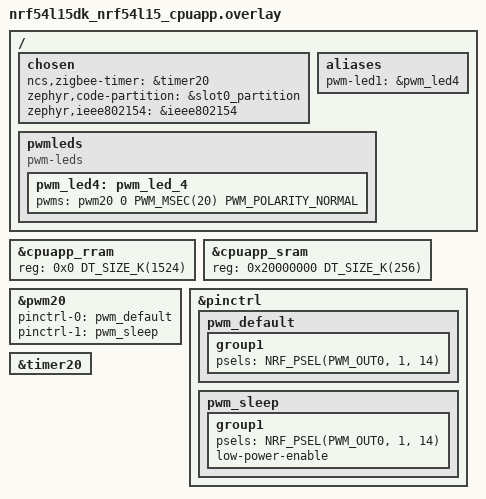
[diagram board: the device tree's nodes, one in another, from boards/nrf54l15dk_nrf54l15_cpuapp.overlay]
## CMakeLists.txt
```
#
# Copyright (c) 2026 Nordic Semiconductor ASA
#
# SPDX-License-Identifier: LicenseRef-Nordic-5-Clause
#

cmake_minimum_required(VERSION 3.20.0)

find_package(Zephyr REQUIRED HINTS $ENV{ZEPHYR_BASE})

project("Matter + Zigbee Light Bulb")

include(${ZEPHYR_CONNECTEDHOMEIP_MODULE_DIR}/config/nrfconnect/app/enable-gnu-std.cmake)
include(${ZEPHYR_NRF_MODULE_DIR}/samples/matter/common/cmake/source_common.cmake)
include(${ZEPHYR_NRF_MODULE_DIR}/samples/matter/common/cmake/data_model.cmake)
include(${ZEPHYR_NRF_MODULE_DIR}/samples/matter/common/cmake/zap_helpers.cmake)
ncs_get_zap_parent_dir(ZAP_PARENT_DIR)

target_include_directories(app PRIVATE
	src
	include
	${ZAP_PARENT_DIR}
)

target_compile_options(app PRIVATE -Wno-deprecated-declarations)

target_sources(app PRIVATE
	src/main.cpp
	src/app_task_zigbee.cpp
	src/app_task_matter.cpp
	src/zboss_mem_globals.c
	src/zcl_callbacks.cpp
	${CHIP_ROOT}/src/app/persistence/DeferredAttributePersistenceProvider.cpp
)

# LTO link: zb_memconfig.o from prebuilts is plain ELF (weak gc_*); strong gc_*
# in zb_mem_config_context.h must not be LTO bytecode or ld warns about symbol size.
if(CONFIG_LTO)
	set_source_files_properties(
		src/zboss_mem_globals.c
		PROPERTIES COMPILE_OPTIONS -fno-lto
	)
endif()

ncs_configure_data_model()
```

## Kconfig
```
#
# Copyright (c) 2026 Nordic Semiconductor ASA
#
# SPDX-License-Identifier: LicenseRef-Nordic-5-Clause
#

# Sample configuration used for Thread networking
if OPENTHREAD

choice OPENTHREAD_NORDIC_LIBRARY_CONFIGURATION
	default OPENTHREAD_NORDIC_LIBRARY_FTD
endchoice

choice OPENTHREAD_DEVICE_TYPE
	default OPENTHREAD_FTD
endchoice

endif # OPENTHREAD

if ZIGBEE_BT_DFU

config BT_DEVICE_NAME
	default "Zigbee_Bulb"

endif # ZIGBEE_BT_DFU

config MPSL_THREAD_COOP_PRIO
	default 8

source "$(ZEPHYR_CONNECTEDHOMEIP_MODULE_DIR)/config/nrfconnect/chip-module/Kconfig.features"
source "$(ZEPHYR_CONNECTEDHOMEIP_MODULE_DIR)/config/nrfconnect/chip-module/Kconfig.defaults"
source "$(ZEPHYR_NRF_MODULE_DIR)/samples/matter/common/src/Kconfig"

source "Kconfig.zephyr"
```

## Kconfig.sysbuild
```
#
# Copyright (c) 2024 Nordic Semiconductor
#
# SPDX-License-Identifier: LicenseRef-Nordic-5-Clause
#

config NRF_DEFAULT_IPC_RADIO
	default y

# Enable IEEE802.15.4 serialization to network core for Zigbee
config NETCORE_IPC_RADIO_IEEE802154
	default y if SOC_SERIES_NRF53

#### Bootloader
choice BOOTLOADER
	default BOOTLOADER_MCUBOOT
endchoice

if BOOTLOADER_MCUBOOT

#### DFU multi-image support
config DFU_MULTI_IMAGE_PACKAGE_BUILD
	default y

config DFU_MULTI_IMAGE_PACKAGE_APP
	default y

#### DFU dual core configuration
if SOC_SERIES_NRF53

config PM_EXTERNAL_FLASH_MCUBOOT_SECONDARY
	default y

config MCUBOOT_UPDATEABLE_IMAGES
	default 2

choice MCUBOOT_MODE
	default MCUBOOT_MODE_OVERWRITE_ONLY
endchoice

config SECURE_BOOT_NETCORE
	default y

config NETCORE_APP_UPDATE
	default y

config DFU_MULTI_IMAGE_PACKAGE_NET
	default y

endif # SOC_SERIES_NRF53

endif # BOOTLOADER_MCUBOOT

source "${ZEPHYR_BASE}/share/sysbuild/Kconfig"
```

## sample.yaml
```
sample:
  description: Combined Matter + Zigbee dimmable light bulb sample
  name: Matter + Zigbee Light bulb
common:
  tags:
    - ci_build
    - smoke
    - sysbuild
    - ci_samples_matter_zigbee
tests:
  sample.matter_zigbee.light_bulb:
    sysbuild: true
    build_only: true
    extra_args:
      - SNIPPET=ext_flash
    integration_platforms:
      - nrf54l15dk/nrf54l15/cpuapp
      - nrf54lm20dk/nrf54lm20b/cpuapp
    platform_allow:
      - nrf54l15dk/nrf54l15/cpuapp
      - nrf54lm20dk/nrf54lm20a/cpuapp
      - nrf54lm20dk/nrf54lm20b/cpuapp
  sample.matter_zigbee.light_bulb.int_flash:
    sysbuild: true
    build_only: true
    integration_platforms:
      - nrf54lm20dk/nrf54lm20b/cpuapp
    platform_allow:
      - nrf54lm20dk/nrf54lm20a/cpuapp
      - nrf54lm20dk/nrf54lm20b/cpuapp
  sample.matter_zigbee.light_bulb.release:
    sysbuild: true
    build_only: true
    extra_args:
      - SNIPPET=ext_flash
      - EXTRA_CONF_FILE=release.conf
    platform_allow:
      - nrf54l15dk/nrf54l15/cpuapp
      - nrf54lm20dk/nrf54lm20a/cpuapp
      - nrf54lm20dk/nrf54lm20b/cpuapp
    tags:
      - no_integration
  sample.matter_zigbee.light_bulb.touchlink:
    sysbuild: true
    build_only: true
    extra_args:
      - SNIPPET=ext_flash
      - CONFIG_ZIGBEE_TOUCHLINK_TARGET=y
    platform_allow:
      - nrf54l15dk/nrf54l15/cpuapp
      - nrf54lm20dk/nrf54lm20a/cpuapp
      - nrf54lm20dk/nrf54lm20b/cpuapp
    tags:
      - no_integration
  sample.matter_zigbee.light_bulb.zigbee_fota:
    sysbuild: true
    build_only: true
    extra_args:
      - SNIPPET=ext_flash
      - EXTRA_CONF_FILE=zigbee_fota.conf
    platform_allow:
      - nrf54l15dk/nrf54l15/cpuapp
      - nrf54lm20dk/nrf54lm20a/cpuapp
      - nrf54lm20dk/nrf54lm20b/cpuapp
    tags:
      - no_integration
```

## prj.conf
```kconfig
#
# Copyright (c) 2026 Nordic Semiconductor ASA
#
# SPDX-License-Identifier: LicenseRef-Nordic-5-Clause
#
# Debug configuration for combined Zigbee + Matter + Thread (PoC)
# Includes logging, console, and debug features

CONFIG_MATTER_ZIGBEE_ADD_ON=y

# Base sample configs
CONFIG_NCS_SAMPLES_DEFAULTS=y

CONFIG_UART_INTERRUPT_DRIVEN=y
CONFIG_SERIAL=y
CONFIG_GPIO=y
CONFIG_PWM=y

# Console
CONFIG_CONSOLE=y
CONFIG_UART_CONSOLE=y

# CONFIG_HEAP_MEM_POOL_SIZE=4096
CONFIG_MAIN_THREAD_PRIORITY=7

#######################
# Zigbee Configuration
#######################

CONFIG_ZIGBEE_ADD_ON=y
CONFIG_ZIGBEE_APP_UTILS=y
# Show Zigbee init/recovery logs (Device first start, network steering recovery).
CONFIG_ZIGBEE_APP_UTILS_LOG_LEVEL_INF=y
CONFIG_ZIGBEE_ROLE_ROUTER=y

# Scene extension
CONFIG_ZIGBEE_SCENES=y

# Enable DK LED and Buttons library
CONFIG_DK_LIBRARY=y

# This example requires more workqueue stack
CONFIG_SYSTEM_WORKQUEUE_STACK_SIZE=2048

CONFIG_ZBOSS_OSIF_LOG_LEVEL_INF=y
CONFIG_MATTER_ZIGBEE_COEXISTENCE_LOG_LEVEL_INF=y

#######################
# Zigbee FOTA Configuration
#######################

# FIXME: Disabled Zigbee FOTA for initial development
# # Enable Zigbee FOTA library
# CONFIG_ZIGBEE_FOTA=y
# CONFIG_ZIGBEE_FOTA_HW_VERSION=52
# CONFIG_ZIGBEE_FOTA_ENDPOINT=5
# CONFIG_MCUBOOT_IMGTOOL_SIGN_VERSION="1.0.0"
# CONFIG_ZIGBEE_FOTA_COMMENT="light_bulb_matter"

# # Ensure an MCUboot-compatible binary is generated.
# CONFIG_IMG_MANAGER=y
# CONFIG_STREAM_FLASH=y
# CONFIG_DFU_TARGET_MCUBOOT=y
# CONFIG_IMG_ERASE_PROGRESSIVELY=y
# CONFIG_ZIGBEE_FOTA_PROGRESS_EVT=y

# # Increase the number of RX buffers for FOTA
# CONFIG_NRF_802154_RX_BUFFERS=32

#######################
# Matter Configuration
#######################

# Enable CHIP (Matter)
CONFIG_CHIP=y
CONFIG_CHIP_PROJECT_CONFIG="include/chip_project_config.h"
CONFIG_CHIP_DEVICE_PRODUCT_NAME="Matter Zigbee Light Bulb"

# Configure ZAP file
CONFIG_NCS_SAMPLE_MATTER_ZAP_FILE_PATH="${APPLICATION_CONFIG_DIR}/src/matter_zap/light_bulb.zap"

# 32773 == 0x8005 (example lighting-app)
CONFIG_CHIP_DEVICE_PRODUCT_ID=32773
CONFIG_STD_CPP17=y

# Enable Matter pairing automatically on application start.
CONFIG_CHIP_ENABLE_PAIRING_AUTOSTART=y

# Enable Matter extended announcement and increase duration to 1 hour.
CONFIG_CHIP_BLE_EXT_ADVERTISING=y
CONFIG_CHIP_BLE_ADVERTISING_DURATION=60

CONFIG_BT_DEVICE_NAME="MatterZigbeeLb"

# Other settings
CONFIG_THREAD_NAME=y
CONFIG_MPU_STACK_GUARD=y
CONFIG_RESET_ON_FATAL_ERROR=n

# Reduce application size
CONFIG_USE_SEGGER_RTT=n

# Increase system workqueue stack for combined protocols (with Thread)
CONFIG_SYSTEM_WORKQUEUE_STACK_SIZE=6144

# Must be a preemptible priority (0–15), not cooperative (-1). With -1, ZBOSS is
# coop priority -1 and is outranked by MPSL Work (prio -8), so it never runs.
# State 128 = _THREAD_QUEUED (runnable); ZBOSS stays queued and never gets CPU.
CONFIG_ZBOSS_DEFAULT_THREAD_PRIORITY=1
CONFIG_ZBOSS_DEFAULT_THREAD_STACK_SIZE=6144

# Libc malloc arena required for Zigbee + Matter coexistence.
# - 0: no libc heap -> Matter init fails (malloc/calloc used during init).
# - -1: "all remaining RAM" -> on this build the computed heap extends past
#   valid RAM and triggers a precise data bus fault in sys_heap_init().
# - Positive value: static BSS heap of that size -> valid heap, no fault.
# Matter uses CHIP_MALLOC_SYS_HEAP for its own allocations; this arena
# covers libc malloc() used elsewhere (init, Zephyr, Zigbee, etc.).
CONFIG_COMMON_LIBC_MALLOC_ARENA_SIZE=-1

## PoC Configuration ##
# Keep Matter shell disabled to avoid getopt conflicts
CONFIG_CHIP_LIB_SHELL=n
CONFIG_NCS_SAMPLE_MATTER_TEST_SHELL=n

# Radio dispatcher 
CONFIG_NRF_802154_CALLBACKS_DISPATCHER=y

# We need it to disable ZBOSS thread
CONFIG_ZIGBEE_DEBUG_FUNCTIONS=y

CONFIG_CHIP_FACTORY_DATA_BUILD=y

# DFU over Bluetooth LE SMP
CONFIG_CHIP_DFU_OVER_BT_SMP=y
CONFIG_NCS_SAMPLE_MATTER_CUSTOM_BLUETOOTH_ADVERTISING=y
```

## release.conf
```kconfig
#
# Copyright (c) 2026 Nordic Semiconductor ASA
#
# SPDX-License-Identifier: LicenseRef-Nordic-5-Clause
#
# Release/size-optimization configuration for combined Zigbee + Matter + Thread (PoC)
# Disables logging, console, and other debug features to reduce flash usage

#######################
# Release Optimizations
#######################

# Disable all debug features
CONFIG_USE_SEGGER_RTT=n
CONFIG_SHELL=n
CONFIG_OPENTHREAD_SHELL=n
CONFIG_CONSOLE=n
CONFIG_UART_CONSOLE=n
CONFIG_SERIAL=n
CONFIG_UART_INTERRUPT_DRIVEN=n
CONFIG_LOG=n
CONFIG_LOG_MODE_MINIMAL=n
CONFIG_ASSERT_VERBOSE=n
CONFIG_ASSERT_NO_FILE_INFO=y
CONFIG_PRINTK=n
CONFIG_PRINTK_SYNC=n
CONFIG_BOOT_BANNER=n

# Enable LTO to decrease the flash usage
CONFIG_LTO=y
CONFIG_ISR_TABLES_LOCAL_DECLARATION=y

# Additional size optimizations
CONFIG_SIZE_OPTIMIZATIONS=y
CONFIG_COMPILER_OPT="-Os"
```

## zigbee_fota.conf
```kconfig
#
# Copyright (c) 2026 Nordic Semiconductor ASA
#
# SPDX-License-Identifier: LicenseRef-Nordic-5-Clause
#

# Enable Zigbee FOTA library
CONFIG_ZIGBEE_FOTA=y
CONFIG_ZIGBEE_FOTA_HW_VERSION=54
CONFIG_ZIGBEE_FOTA_ENDPOINT=5
CONFIG_MCUBOOT_IMGTOOL_SIGN_VERSION="1.0.0"
CONFIG_ZIGBEE_FOTA_COMMENT="light_bulb"

# Ensure an MCUboot-compatible binary is generated.
CONFIG_IMG_MANAGER=y
CONFIG_STREAM_FLASH=y
CONFIG_DFU_TARGET_MCUBOOT=y
CONFIG_IMG_ERASE_PROGRESSIVELY=y
CONFIG_ZIGBEE_FOTA_PROGRESS_EVT=y

# Increase the number of RX buffers for FOTA
CONFIG_NRF_802154_RX_BUFFERS=32
```

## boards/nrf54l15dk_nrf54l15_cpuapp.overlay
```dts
/*
 * Copyright (c) 2026 Nordic Semiconductor ASA
 *
 * SPDX-License-Identifier: LicenseRef-Nordic-5-Clause
 */

#include <nrf54l15dk_cpuapp_partitions.dtsi>

/ {
	chosen {
		ncs,zigbee-timer = &timer20;
		zephyr,code-partition = &slot0_partition;
		zephyr,ieee802154 = &ieee802154;
	};

	aliases {
		/* PWM on P1.14 (DK_LED4 / board LED 3). */
		pwm-led1 = &pwm_led4;
	};

	pwmleds {
		compatible = "pwm-leds";

		pwm_led4: pwm_led_4 {
			pwms = <&pwm20 0 PWM_MSEC(20) PWM_POLARITY_NORMAL>;
		};
	};
};

&cpuapp_rram {
	reg = <0x0 DT_SIZE_K(1524)>;
};

&cpuapp_sram {
	reg = <0x20000000 DT_SIZE_K(256)>;
	ranges = <0x0 0x20000000 0x40000>;
};

&pwm20 {
	status = "okay";
	pinctrl-0 = <&pwm_default>;
	pinctrl-1 = <&pwm_sleep>;
	pinctrl-names = "default", "sleep";
};

&pinctrl {
	pwm_default: pwm_default {
		group1 {
			psels = <NRF_PSEL(PWM_OUT0, 1, 14)>;
		};
	};

	pwm_sleep: pwm_sleep {
		group1 {
			psels = <NRF_PSEL(PWM_OUT0, 1, 14)>;
			low-power-enable;
		};
	};
};

&timer20 {
	status = "okay";
};
```

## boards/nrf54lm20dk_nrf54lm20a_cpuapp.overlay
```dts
/*
 * Copyright (c) 2026 Nordic Semiconductor ASA
 *
 * SPDX-License-Identifier: LicenseRef-Nordic-5-Clause
 */

#include <nrf54lm20_cpuapp_partitions.dtsi>
#include <nrf54lm20dk_cpuapp_partitions.dtsi>

/ {
	chosen {
		ncs,zigbee-timer = &timer23;
		ncs,zboss-trace-uart = &uart20;
	};

	aliases {
		/* PWM on P1.28 (DK_LED4 / board LED 3). */
		pwm-led1 = &pwm_led4;
	};

	pwmleds {
		compatible = "pwm-leds";
		pwm_led4: pwm_led_4 {
			pwms = <&pwm20 0 PWM_MSEC(20) PWM_POLARITY_NORMAL>;
		};
	};
};

&pwm20 {
	status = "okay";
	pinctrl-0 = <&pwm_default>;
	pinctrl-1 = <&pwm_sleep>;
	pinctrl-names = "default", "sleep";
};

&pinctrl {
	pwm_default: pwm_default {
		group1 {
			psels = <NRF_PSEL(PWM_OUT0, 1, 28)>;
		};
	};
	pwm_sleep: pwm_sleep {
		group1 {
			psels = <NRF_PSEL(PWM_OUT0, 1, 28)>;
			low-power-enable;
		};
	};
};

&timer23 {
	status = "okay";
};
```

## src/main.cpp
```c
/*
 * Copyright (c) 2026 Nordic Semiconductor ASA
 *
 * SPDX-License-Identifier: LicenseRef-Nordic-5-Clause
 */

/** @file
 *
 * @brief Matter + Zigbee light bulb entry point.
 */

#include "app_task_matter.h"
#include "app_task_zigbee.h"

#include <matter_zigbee_coexistence.h>
#include <matter_zigbee_ui.h>

namespace
{

void matter_start_cb(void)
{
	AppTask::Instance().StartApp();
}

bool app_ui_button_handler(uint32_t button_state, uint32_t has_changed, active_protocol_t active_protocol)
{
	/* Handle button events only for the active protocol. */
	if (active_protocol == PROTOCOL_ZIGBEE) {
		zb_button_handler(button_state, has_changed);
	}

	if (active_protocol == PROTOCOL_MATTER) {
		AppTask::ButtonEventHandler(button_state, has_changed);
	}

	return false;
}

const struct matter_zigbee_ui_callbacks ui_callbacks = {
	.on_button = app_ui_button_handler,
};

const struct matter_zigbee_coexistence_callbacks coexistence_cb = {
	matter_start_cb,
	ZigbeeStart,
	matter_zigbee_ui_register,
};

} /* namespace */

int main(void)
{
	matter_zigbee_ui_set_callbacks(&ui_callbacks);
	return matter_zigbee_coexistence_run(&coexistence_cb);
}
```

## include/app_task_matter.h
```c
/*
 * Copyright (c) 2026 Nordic Semiconductor ASA
 *
 * SPDX-License-Identifier: LicenseRef-Nordic-5-Clause
 */

#pragma once

#include "board/board.h"
#include "pwm/pwm_device.h"

#include <platform/CHIPDeviceLayer.h>

struct k_timer;
struct Identify;

enum class LightingActor : uint8_t { Remote, Button };

struct LightingEvent {
	uint8_t Action;
	LightingActor Actor;
};

class AppTask {
public:
	static AppTask &Instance()
	{
		static AppTask sAppTask;
		return sAppTask;
	};

	CHIP_ERROR StartApp();

	void UpdateClusterState();
	void InitPWMDDevice();
	Nrf::PWMDevice &GetPWMDevice() { return mPWMDevice; }

	static void ButtonEventHandler(Nrf::ButtonState state, Nrf::ButtonMask hasChanged);

private:
	CHIP_ERROR Init();

	static void LightingActionEventHandler(const LightingEvent &event);

	static void ActionInitiated(Nrf::PWMDevice::Action_t action, int32_t actor);
	static void ActionCompleted(Nrf::PWMDevice::Action_t action, int32_t actor);

	Nrf::PWMDevice mPWMDevice;
};
```

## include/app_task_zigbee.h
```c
/*
 * Copyright (c) 2026 Nordic Semiconductor ASA
 *
 * SPDX-License-Identifier: LicenseRef-Nordic-5-Clause
 */

#ifndef APP_TASK_ZIGBEE_H
#define APP_TASK_ZIGBEE_H 1

#include <stdint.h>

#ifdef __cplusplus
extern "C" {
#endif

int ZigbeeStart(void);

#ifdef CONFIG_MATTER_ZIGBEE_COEXISTENCE
/**
 * @brief Sample-specific button handler for Zigbee in combined builds.
 *
 * Invoked from the common UI module when a button event is received.
 * Processes button events when Zigbee is the active protocol and returns
 * immediately when Matter is active.
 *
 * @param button_state  Bitmask containing buttons state.
 * @param has_changed   Bitmask containing buttons that changed state.
 */
void zb_button_handler(uint32_t button_state, uint32_t has_changed);
#endif /* CONFIG_MATTER_ZIGBEE_COEXISTENCE */

#ifdef __cplusplus
}
#endif

#endif /* APP_TASK_ZIGBEE_H */
```

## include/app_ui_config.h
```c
/*
 * Copyright (c) 2026 Nordic Semiconductor ASA
 *
 * SPDX-License-Identifier: LicenseRef-Nordic-5-Clause
 */

#ifndef APP_UI_CONFIG_H_
#define APP_UI_CONFIG_H_

/** @file
 * @brief Light bulb sample UI configuration (buttons and LEDs).
 *
 * Common Matter + Zigbee UI buttons and LEDs are defined in
 * @ref matter_zigbee_ui_config.h. This file adds sample-specific mappings
 * shared by the Matter and Zigbee application tasks.
 */

#include <matter_zigbee_ui_config.h>

#include <zephyr/devicetree.h>

/** Button 3: toggle main light (Matter). */
#define APP_UI_BUTTON_LIGHT_TOGGLE DK_BTN3_MSK

/** Main light output on DK_LED3 (onboard LED 2), driven by PWM when enabled. */
#define APP_UI_LED_MAIN_LIGHT DK_LED3

/** PWM devicetree node for the main light (board overlay: pwm-led1 alias). */
#define APP_UI_PWM_LIGHT_NODE DT_ALIAS(pwm_led1)

#endif /* APP_UI_CONFIG_H_ */
```

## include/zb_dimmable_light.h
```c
/*
 * Copyright (c) 2024 Nordic Semiconductor ASA
 *
 * SPDX-License-Identifier: LicenseRef-Nordic-5-Clause
 */

#ifndef ZB_DIMMABLE_LIGHT_H
#define ZB_DIMMABLE_LIGHT_H 1

/**
 *  @defgroup ZB_DEFINE_DEVICE_DIMMABLE_LIGHT Dimmable Light
 *  @{
 *  @details
 *      - @ref ZB_ZCL_BASIC \n
 *      - @ref ZB_ZCL_IDENTIFY \n
 *      - @ref ZB_ZCL_SCENES \n
 *      - @ref ZB_ZCL_GROUPS \n
 *      - @ref ZB_ZCL_ON_OFF \n
 *      - @ref ZB_ZCL_LEVEL_CONTROL
 */

/** Dimmable Light Device ID */
#define ZB_DIMMABLE_LIGHT_DEVICE_ID 0x0101

/** Dimmable light device version */
#define ZB_DEVICE_VER_DIMMABLE_LIGHT 1

/** @cond internals_doc */

/** Dimmable Light IN (server) clusters number */
#define ZB_DIMMABLE_LIGHT_IN_CLUSTER_NUM 6

/** Dimmable Light OUT (client) clusters number */
#define ZB_DIMMABLE_LIGHT_OUT_CLUSTER_NUM 0

/** Dimmable light total (IN+OUT) cluster number */
#define ZB_DIMMABLE_LIGHT_CLUSTER_NUM (ZB_DIMMABLE_LIGHT_IN_CLUSTER_NUM + ZB_DIMMABLE_LIGHT_OUT_CLUSTER_NUM)

/** Number of attribute for reporting on Dimmable Light device */
#define ZB_DIMMABLE_LIGHT_REPORT_ATTR_COUNT (ZB_ZCL_ON_OFF_REPORT_ATTR_COUNT + ZB_ZCL_LEVEL_CONTROL_REPORT_ATTR_COUNT)

/** Continuous value change attribute count */
#define ZB_DIMMABLE_LIGHT_CVC_ATTR_COUNT 1

/** @endcond */ /* internals_doc */

/**
 * @brief Declare cluster list for Dimmable Light device
 * @param cluster_list_name - cluster list variable name
 * @param basic_attr_list - attribute list for Basic cluster
 * @param identify_attr_list - attribute list for Identify cluster
 * @param groups_attr_list - attribute list for Groups cluster
 * @param scenes_attr_list - attribute list for Scenes cluster
 * @param on_off_attr_list - attribute list for On/Off cluster
 * @param level_control_attr_list - attribute list for Level Control cluster
 */
#define ZB_DECLARE_DIMMABLE_LIGHT_CLUSTER_LIST(cluster_list_name, basic_attr_list, identify_attr_list,                 \
					       groups_attr_list, scenes_attr_list, on_off_attr_list,                   \
					       level_control_attr_list)                                                \
	zb_zcl_cluster_desc_t cluster_list_name[] = {                                                                  \
		ZB_ZCL_CLUSTER_DESC(ZB_ZCL_CLUSTER_ID_IDENTIFY, ZB_ZCL_ARRAY_SIZE(identify_attr_list, zb_zcl_attr_t),  \
				    (identify_attr_list), ZB_ZCL_CLUSTER_SERVER_ROLE, ZB_ZCL_MANUF_CODE_INVALID),      \
		ZB_ZCL_CLUSTER_DESC(ZB_ZCL_CLUSTER_ID_BASIC, ZB_ZCL_ARRAY_SIZE(basic_attr_list, zb_zcl_attr_t),        \
				    (basic_attr_list), ZB_ZCL_CLUSTER_SERVER_ROLE, ZB_ZCL_MANUF_CODE_INVALID),         \
		ZB_ZCL_CLUSTER_DESC(ZB_ZCL_CLUSTER_ID_SCENES, ZB_ZCL_ARRAY_SIZE(scenes_attr_list, zb_zcl_attr_t),      \
				    (scenes_attr_list), ZB_ZCL_CLUSTER_SERVER_ROLE, ZB_ZCL_MANUF_CODE_INVALID),        \
		ZB_ZCL_CLUSTER_DESC(ZB_ZCL_CLUSTER_ID_GROUPS, ZB_ZCL_ARRAY_SIZE(groups_attr_list, zb_zcl_attr_t),      \
				    (groups_attr_list), ZB_ZCL_CLUSTER_SERVER_ROLE, ZB_ZCL_MANUF_CODE_INVALID),        \
		ZB_ZCL_CLUSTER_DESC(ZB_ZCL_CLUSTER_ID_ON_OFF, ZB_ZCL_ARRAY_SIZE(on_off_attr_list, zb_zcl_attr_t),      \
				    (on_off_attr_list), ZB_ZCL_CLUSTER_SERVER_ROLE, ZB_ZCL_MANUF_CODE_INVALID),        \
		ZB_ZCL_CLUSTER_DESC(ZB_ZCL_CLUSTER_ID_LEVEL_CONTROL,                                                   \
				    ZB_ZCL_ARRAY_SIZE(level_control_attr_list, zb_zcl_attr_t),                         \
				    (level_control_attr_list), ZB_ZCL_CLUSTER_SERVER_ROLE, ZB_ZCL_MANUF_CODE_INVALID)  \
	}

/** @cond internals_doc */
/**
 * @brief Declare simple descriptor for Dimmable Light device
 * @param ep_name - endpoint variable name
 * @param ep_id - endpoint ID
 * @param in_clust_num - number of supported input clusters
 * @param out_clust_num - number of supported output clusters
 */
#define ZB_ZCL_DECLARE_HA_DIMMABLE_LIGHT_SIMPLE_DESC(ep_name, ep_id, in_clust_num, out_clust_num)                      \
	ZB_DECLARE_SIMPLE_DESC(in_clust_num, out_clust_num);                                                           \
	ZB_AF_SIMPLE_DESC_TYPE(in_clust_num, out_clust_num)                                                            \
	simple_desc_##ep_name = { ep_id,                                                                               \
				  ZB_AF_HA_PROFILE_ID,                                                                 \
				  ZB_DIMMABLE_LIGHT_DEVICE_ID,                                                         \
				  ZB_DEVICE_VER_DIMMABLE_LIGHT,                                                        \
				  0,                                                                                   \
				  in_clust_num,                                                                        \
				  out_clust_num,                                                                       \
				  {                                                                                    \
					  ZB_ZCL_CLUSTER_ID_BASIC,                                                     \
					  ZB_ZCL_CLUSTER_ID_IDENTIFY,                                                  \
					  ZB_ZCL_CLUSTER_ID_SCENES,                                                    \
					  ZB_ZCL_CLUSTER_ID_GROUPS,                                                    \
					  ZB_ZCL_CLUSTER_ID_ON_OFF,                                                    \
					  ZB_ZCL_CLUSTER_ID_LEVEL_CONTROL,                                             \
				  } }

/** @endcond */ /* internals_doc */

/**
 * @brief Declare endpoint for Dimmable Light device
 * @param ep_name - endpoint variable name
 * @param ep_id - endpoint ID
 * @param cluster_list - endpoint cluster list
 */
#define ZB_DECLARE_DIMMABLE_LIGHT_EP(ep_name, ep_id, cluster_list)                                                     \
	ZB_ZCL_DECLARE_HA_DIMMABLE_LIGHT_SIMPLE_DESC(ep_name, ep_id, ZB_DIMMABLE_LIGHT_IN_CLUSTER_NUM,                 \
						     ZB_DIMMABLE_LIGHT_OUT_CLUSTER_NUM);                               \
	ZBOSS_DEVICE_DECLARE_REPORTING_CTX(reporting_info##ep_name, ZB_DIMMABLE_LIGHT_REPORT_ATTR_COUNT);              \
	ZBOSS_DEVICE_DECLARE_LEVEL_CONTROL_CTX(cvc_alarm_info##ep_name, ZB_DIMMABLE_LIGHT_CVC_ATTR_COUNT);             \
	ZB_AF_DECLARE_ENDPOINT_DESC(ep_name, ep_id, ZB_AF_HA_PROFILE_ID, 0, NULL,                                      \
				    ZB_ZCL_ARRAY_SIZE(cluster_list, zb_zcl_cluster_desc_t), cluster_list,              \
				    (zb_af_simple_desc_1_1_t *)&simple_desc_##ep_name,                                 \
				    ZB_DIMMABLE_LIGHT_REPORT_ATTR_COUNT, reporting_info##ep_name,                      \
				    ZB_DIMMABLE_LIGHT_CVC_ATTR_COUNT, cvc_alarm_info##ep_name)

/** @} */

#endif /* ZB_DIMMABLE_LIGHT_H */
```

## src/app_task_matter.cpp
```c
/*
 * Copyright (c) 2026 Nordic Semiconductor ASA
 *
 * SPDX-License-Identifier: LicenseRef-Nordic-5-Clause
 */

#include "app_task_matter.h"

#include "app/matter_init.h"
#include "app/task_executor.h"

#if defined(CONFIG_PWM)
#include "pwm/pwm_device.h"
#endif

#include <matter_zigbee_ui_matter_identify.h>
#include <matter_zigbee_ui.h>
#include <matter_zigbee_ui_config.h>

#include "app_ui_config.h"

#include <zephyr/logging/log.h>

#include <app-common/zap-generated/attributes/Accessors.h>
#include <app/persistence/AttributePersistenceProviderInstance.h>
#include <app/persistence/DefaultAttributePersistenceProvider.h>
#include <app/persistence/DeferredAttributePersistenceProvider.h>
#include <app/server/Server.h>
#include <setup_payload/OnboardingCodesUtil.h>

#if defined(CONFIG_MATTER_ZIGBEE_COEXISTENCE)
#include <matter_zigbee_coexistence.h>
#endif

LOG_MODULE_DECLARE(app, CONFIG_CHIP_APP_LOG_LEVEL);

using namespace ::chip;
using namespace ::chip::app;
using namespace ::chip::DeviceLayer;

namespace
{
constexpr EndpointId kLightEndpointId = 1;
constexpr uint8_t kDefaultMinLevel = 0;
constexpr uint8_t kDefaultMaxLevel = 254;

MatterIdentifyCluster sIdentifyCluster(kLightEndpointId, true);

#if defined(CONFIG_PWM)
const struct pwm_dt_spec sLightPwmDevice = PWM_DT_SPEC_GET(APP_UI_PWM_LIGHT_NODE);
#endif

/* Define a custom attribute persister which makes actual write of the
 * CurrentLevel attribute value to the non-volatile storage only when it has
 * remained constant for 5 seconds. This is to reduce the flash wearout when the
 * attribute changes frequently as a result of MoveToLevel command.
 * DeferredAttribute object describes a deferred attribute, but also holds a
 * buffer with a value to be written, so it must live so long as the
 * DeferredAttributePersistenceProvider object.
 */
DeferredAttribute gCurrentLevelPersister(ConcreteAttributePath(kLightEndpointId, Clusters::LevelControl::Id,
							       Clusters::LevelControl::Attributes::CurrentLevel::Id));

/* Deferred persistence will be auto-initialized as soon as the default
 * persistence is initialized */
DefaultAttributePersistenceProvider gSimpleAttributePersistence;
DeferredAttributePersistenceProvider gDeferredAttributePersister(gSimpleAttributePersistence,
								 Span<DeferredAttribute>(&gCurrentLevelPersister, 1),
								 System::Clock::Milliseconds32(5000));

} /* namespace */

void AppTask::LightingActionEventHandler(const LightingEvent &event)
{
#if defined(CONFIG_PWM)
	Nrf::PWMDevice::Action_t action = Nrf::PWMDevice::INVALID_ACTION;
	int32_t actor = 0;
	if (event.Actor == LightingActor::Button) {
		action = Instance().mPWMDevice.IsTurnedOn() ? Nrf::PWMDevice::OFF_ACTION : Nrf::PWMDevice::ON_ACTION;
		actor = static_cast<int32_t>(event.Actor);
	}

	if (action == Nrf::PWMDevice::INVALID_ACTION || !Instance().mPWMDevice.InitiateAction(action, actor, NULL)) {
		LOG_INF("An action could not be initiated.");
	}
#else
	matter_zigbee_ui_led_toggle(APP_UI_LED_MAIN_LIGHT);
#endif
}

void AppTask::ButtonEventHandler(Nrf::ButtonState state, Nrf::ButtonMask hasChanged)
{
	if ((APP_UI_BUTTON_LIGHT_TOGGLE & hasChanged) & state) {
		Nrf::PostTask([] {
			LightingEvent event;
			event.Actor = LightingActor::Button;
			LightingActionEventHandler(event);
		});
	}
}

#if defined(CONFIG_PWM)
void AppTask::ActionInitiated(Nrf::PWMDevice::Action_t action, int32_t actor)
{
	if (action == Nrf::PWMDevice::ON_ACTION) {
		LOG_INF("Turn On Action has been initiated");
	} else if (action == Nrf::PWMDevice::OFF_ACTION) {
		LOG_INF("Turn Off Action has been initiated");
	} else if (action == Nrf::PWMDevice::LEVEL_ACTION) {
		LOG_INF("Level Action has been initiated");
	}
}

void AppTask::ActionCompleted(Nrf::PWMDevice::Action_t action, int32_t actor)
{
	if (action == Nrf::PWMDevice::ON_ACTION) {
		LOG_INF("Turn On Action has been completed");
	} else if (action == Nrf::PWMDevice::OFF_ACTION) {
		LOG_INF("Turn Off Action has been completed");
	} else if (action == Nrf::PWMDevice::LEVEL_ACTION) {
		LOG_INF("Level Action has been completed");
	}

	if (actor == static_cast<int32_t>(LightingActor::Button)) {
		Instance().UpdateClusterState();
	}
}
#endif /* CONFIG_PWM */

void AppTask::UpdateClusterState()
{
	SystemLayer().ScheduleLambda([this] {
#if defined(CONFIG_PWM)
		/* write the new on/off value */
		Protocols::InteractionModel::Status status =
			Clusters::OnOff::Attributes::OnOff::Set(kLightEndpointId, mPWMDevice.IsTurnedOn());
#else
		Protocols::InteractionModel::Status status = Clusters::OnOff::Attributes::OnOff::Set(
			kLightEndpointId, matter_zigbee_ui_led_get(APP_UI_LED_MAIN_LIGHT));
#endif
		if (status != Protocols::InteractionModel::Status::Success) {
			LOG_ERR("Updating on/off cluster failed: %x", to_underlying(status));
		}

#if defined(CONFIG_PWM)
		/* write the current level */
		status = Clusters::LevelControl::Attributes::CurrentLevel::Set(kLightEndpointId, mPWMDevice.GetLevel());
#else
		/* write the current level */
		if (matter_zigbee_ui_led_get(APP_UI_LED_MAIN_LIGHT)) {
			status = Clusters::LevelControl::Attributes::CurrentLevel::Set(kLightEndpointId, 100);
		} else {
			status = Clusters::LevelControl::Attributes::CurrentLevel::Set(kLightEndpointId, 0);
		}
#endif

		if (status != Protocols::InteractionModel::Status::Success) {
			LOG_ERR("Updating level cluster failed: %x", to_underlying(status));
		}
	});
}

void AppTask::InitPWMDDevice()
{
#if defined(CONFIG_PWM)
	/* Initialize lighting device (PWM) */
	uint8_t minLightLevel = kDefaultMinLevel;
	Clusters::LevelControl::Attributes::MinLevel::Get(kLightEndpointId, &minLightLevel);

	uint8_t maxLightLevel = kDefaultMaxLevel;
	Clusters::LevelControl::Attributes::MaxLevel::Get(kLightEndpointId, &maxLightLevel);

	Clusters::LevelControl::Attributes::CurrentLevel::TypeInfo::Type currentLevel;
	Clusters::LevelControl::Attributes::CurrentLevel::Get(kLightEndpointId, currentLevel);

	int ret =
		mPWMDevice.Init(&sLightPwmDevice, minLightLevel, maxLightLevel, currentLevel.ValueOr(kDefaultMaxLevel));
	if (ret != 0) {
		LOG_ERR("Failed to initialize PWD device.");
	}

	mPWMDevice.SetCallbacks(ActionInitiated, ActionCompleted);
#endif
}

CHIP_ERROR AppTask::Init()
{
	/* Initialize Matter stack */
	Nrf::Matter::InitData initData{};
	initData.mPostServerInitClbk = []() {
		app::SetAttributePersistenceProvider(&gDeferredAttributePersister);
		gSimpleAttributePersistence.Init(Nrf::Matter::GetPersistentStorageDelegate());
		return CHIP_NO_ERROR;
	};
#if defined(CONFIG_MATTER_ZIGBEE_COEXISTENCE)
	initData.mPreServerInitClbk = []() -> CHIP_ERROR {
		matter_zigbee_coexistence_pre_server_init();
		return CHIP_NO_ERROR;
	};
#endif
	ReturnErrorOnFailure(Nrf::Matter::PrepareServer(initData));

	ReturnErrorOnFailure(sIdentifyCluster.Init());

	ReturnErrorOnFailure(Nrf::Matter::StartServer());

#if defined(CONFIG_MATTER_ZIGBEE_COEXISTENCE)
	matter_zigbee_coexistence_on_server_started();
#endif

	return CHIP_NO_ERROR;
}

CHIP_ERROR AppTask::StartApp()
{
	ReturnErrorOnFailure(Init());

	while (true) {
		Nrf::DispatchNextTask();
	}

	return CHIP_NO_ERROR;
}
```

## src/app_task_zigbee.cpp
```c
/*
 * Copyright (c) 2026 Nordic Semiconductor ASA
 *
 * SPDX-License-Identifier: LicenseRef-Nordic-5-Clause
 */

/** @file
 *
 * @brief Simple Zigbee light bulb implementation.
 */

#include "app_task_zigbee.h"

#ifdef CONFIG_MATTER_ZIGBEE_COEXISTENCE
#include <matter_zigbee_coexistence.h>
#include <matter_zigbee_protocol_state.h>
#endif

#include <matter_zigbee_ui_config.h>
#include <matter_zigbee_ui.h>

#include "app_ui_config.h"

#include <soc.h>
#include <zephyr/device.h>
#include <zephyr/drivers/pwm.h>
#include <zephyr/kernel.h>
#include <zephyr/logging/log.h>
#include <zephyr/sys/util.h>
#ifdef CONFIG_ZIGBEE_SCENES
#include <zephyr/settings/settings.h>
#endif
#include <zephyr/types.h>

#if defined(CONFIG_ZIGBEE_FOTA) || defined(CONFIG_ZIGBEE_BT_DFU)
#include <zephyr/dfu/mcuboot.h>
#endif

#include <ram_pwrdn.h>

extern "C" {
#include "zb_dimmable_light.h"
#include <dk_buttons_and_leds.h>
#include <zb_nrf_platform.h>
#include <zboss_api.h>
#include <zboss_api_addons.h>
#include <zigbee/zigbee_app_utils.h>
#include <zigbee/zigbee_error_handler.h>
#ifdef CONFIG_ZIGBEE_SCENES
#include <zigbee/zigbee_zcl_scenes.h>
#endif
#if CONFIG_ZIGBEE_FOTA
#include <zigbee/zigbee_fota.h>
#endif
#ifdef CONFIG_ZIGBEE_BT_DFU
#include <zigbee/zigbee_bt_dfu.h>
#endif
}

#if CONFIG_ZIGBEE_FOTA
#include <zephyr/sys/reboot.h>
#endif

/* Device endpoint, used to receive light controlling commands. */
#define DIMMABLE_LIGHT_ENDPOINT 10

/* Version of the application software (1 byte). */
#define BULB_INIT_BASIC_APP_VERSION 01

/* Version of the implementation of the Zigbee stack (1 byte). */
#define BULB_INIT_BASIC_STACK_VERSION 10

/* Version of the hardware of the device (1 byte). */
#define BULB_INIT_BASIC_HW_VERSION 11

/* Manufacturer name (32 bytes). */
#define BULB_INIT_BASIC_MANUF_NAME "Nordic"

/* Model number assigned by manufacturer (32-bytes long string). */
#define BULB_INIT_BASIC_MODEL_ID "Dimable_Light_v0.1"

/* First 8 bytes specify the date of manufacturer of the device
 * in ISO 8601 format (YYYYMMDD). The rest (8 bytes) are manufacturer specific.
 */
#define BULB_INIT_BASIC_DATE_CODE "20200329"

/* Type of power sources available for the device.
 * For possible values see section 3.2.2.2.8 of ZCL specification.
 */
#define BULB_INIT_BASIC_POWER_SOURCE ZB_ZCL_BASIC_POWER_SOURCE_DC_SOURCE

/* Describes the physical location of the device (16 bytes).
 * May be modified during commissioning process.
 */
#define BULB_INIT_BASIC_LOCATION_DESC "Office desk"

/* Describes the type of physical environment.
 * For possible values see section 3.2.2.2.10 of ZCL specification.
 */
#define BULB_INIT_BASIC_PH_ENV ZB_ZCL_BASIC_ENV_UNSPECIFIED

#if DT_NODE_HAS_STATUS(APP_UI_PWM_LIGHT_NODE, okay)
static const struct pwm_dt_spec led_pwm = PWM_DT_SPEC_GET(APP_UI_PWM_LIGHT_NODE);
#else
#error "Choose supported PWM driver"
#endif

/* Led PWM period, calculated for 100 Hz signal - in microseconds. */
#define LED_PWM_PERIOD_US (USEC_PER_SEC / 100U)

#ifndef ZB_ROUTER_ROLE
#error Define ZB_ROUTER_ROLE to compile router source code.
#endif

LOG_MODULE_REGISTER(app, CONFIG_CHIP_APP_LOG_LEVEL);

/* Main application customizable context.
 * Stores all settings and static values.
 */
typedef struct {
	zb_zcl_basic_attrs_ext_t basic_attr;
	zb_zcl_identify_attrs_t identify_attr;
	zb_zcl_scenes_attrs_t scenes_attr;
	zb_zcl_groups_attrs_t groups_attr;
	zb_zcl_on_off_attrs_t on_off_attr;
	zb_zcl_level_control_attrs_t level_control_attr;
} bulb_device_ctx_t;

/* Zigbee device application context storage. */
static bulb_device_ctx_t dev_ctx;

/* Last non-zero brightness used when turning on with CurrentLevel == 0. */
static zb_uint8_t s_last_on_level = ZB_ZCL_LEVEL_CONTROL_LEVEL_MAX_VALUE;

ZB_ZCL_DECLARE_IDENTIFY_ATTRIB_LIST(identify_attr_list, &dev_ctx.identify_attr.identify_time);

ZB_ZCL_DECLARE_GROUPS_ATTRIB_LIST(groups_attr_list, &dev_ctx.groups_attr.name_support);

ZB_ZCL_DECLARE_SCENES_ATTRIB_LIST(scenes_attr_list, &dev_ctx.scenes_attr.scene_count,
				  &dev_ctx.scenes_attr.current_scene, &dev_ctx.scenes_attr.current_group,
				  &dev_ctx.scenes_attr.scene_valid, &dev_ctx.scenes_attr.name_support);

ZB_ZCL_DECLARE_BASIC_ATTRIB_LIST_EXT(basic_attr_list, &dev_ctx.basic_attr.zcl_version, &dev_ctx.basic_attr.app_version,
				     &dev_ctx.basic_attr.stack_version, &dev_ctx.basic_attr.hw_version,
				     dev_ctx.basic_attr.mf_name, dev_ctx.basic_attr.model_id,
				     dev_ctx.basic_attr.date_code, &dev_ctx.basic_attr.power_source,
				     dev_ctx.basic_attr.location_id, &dev_ctx.basic_attr.ph_env,
				     dev_ctx.basic_attr.sw_ver);

/* On/Off cluster attributes additions data */
ZB_ZCL_DECLARE_ON_OFF_ATTRIB_LIST(on_off_attr_list, &dev_ctx.on_off_attr.on_off);

ZB_ZCL_DECLARE_LEVEL_CONTROL_ATTRIB_LIST(level_control_attr_list, &dev_ctx.level_control_attr.current_level,
					 &dev_ctx.level_control_attr.remaining_time);

ZB_DECLARE_DIMMABLE_LIGHT_CLUSTER_LIST(dimmable_light_clusters, basic_attr_list, identify_attr_list, groups_attr_list,
				       scenes_attr_list, on_off_attr_list, level_control_attr_list);

ZB_DECLARE_DIMMABLE_LIGHT_EP(dimmable_light_ep, DIMMABLE_LIGHT_ENDPOINT, dimmable_light_clusters);

#ifndef CONFIG_ZIGBEE_FOTA
ZBOSS_DECLARE_DEVICE_CTX_1_EP(dimmable_light_ctx, dimmable_light_ep);
#else

#if DIMMABLE_LIGHT_ENDPOINT == CONFIG_ZIGBEE_FOTA_ENDPOINT
#error "Light bulb and Zigbee OTA endpoints should be different."
#endif

extern zb_af_endpoint_desc_t zigbee_fota_client_ep;
ZBOSS_DECLARE_DEVICE_CTX_2_EP(dimmable_light_ctx, zigbee_fota_client_ep, dimmable_light_ep);
#endif /* CONFIG_ZIGBEE_FOTA */

/**@brief Starts identifying the device.
 *
 * @param  bufid  Unused parameter, required by ZBOSS scheduler API.
 */
static void start_identifying(zb_bufid_t bufid)
{
	ZVUNUSED(bufid);

	if (ZB_JOINED()) {
		/* Check if endpoint is in identifying mode,
		 * if not, put desired endpoint in identifying mode.
		 */
		if (dev_ctx.identify_attr.identify_time == ZB_ZCL_IDENTIFY_IDENTIFY_TIME_DEFAULT_VALUE) {
			zb_ret_t zb_err_code = zb_bdb_finding_binding_target(DIMMABLE_LIGHT_ENDPOINT);

			if (zb_err_code == RET_OK) {
				LOG_INF("Enter identify mode");
			} else if (zb_err_code == RET_INVALID_STATE) {
				LOG_WRN("RET_INVALID_STATE - Cannot enter identify mode");
			} else {
				ZB_ERROR_CHECK(zb_err_code);
			}
		} else {
			LOG_INF("Cancel identify mode");
			zb_bdb_finding_binding_target_cancel();
		}
	} else {
		LOG_WRN("Device not in a network - cannot enter identify mode");
	}
}

/**@brief Implementation of button event handling for the Zigbee bulb.
 *
 * In combined Matter+Zigbee builds the handler returns early when Matter is
 * the active protocol so Matter's own handlers (registered by Board::Init())
 * keep full ownership of the buttons.
 */
static void zb_button_handler_impl(uint32_t button_state, uint32_t has_changed)
{
	if (MATTER_ZIGBEE_UI_BUTTON_IDENTIFY & has_changed) {
		if (MATTER_ZIGBEE_UI_BUTTON_IDENTIFY & button_state) {
			/* Button changed its state to pressed */
		} else {
			/* Button changed its state to released */
			if (was_factory_reset_done()) {
				/* The long press was for Factory Reset */
				LOG_DBG("After Factory Reset - ignore button release");
			} else {
				/* Button released before Factory Reset */

				/* Start identification mode */
				ZB_SCHEDULE_APP_CALLBACK(start_identifying, 0);
			}
		}
	}
}

#ifdef CONFIG_MATTER_ZIGBEE_COEXISTENCE
extern "C" void zb_button_handler(uint32_t button_state, uint32_t has_changed)
{
	zb_button_handler_impl(button_state, has_changed);
}
#endif /* CONFIG_MATTER_ZIGBEE_COEXISTENCE */

/**@brief Sets brightness of bulb luminous executive element
 *
 * @param[in] brightness_level Brightness level, allowed values 0 ... 255,
 *                             0 - turn off, 255 - full brightness.
 */
static void light_bulb_set_brightness(zb_uint8_t brightness_level)
{
	uint32_t pulse = brightness_level * LED_PWM_PERIOD_US / 255U;

	if (pwm_set_dt(&led_pwm, PWM_USEC(LED_PWM_PERIOD_US), PWM_USEC(pulse))) {
		LOG_ERR("Pwm led 3 set fails:\n");
		return;
	}
}

/**@brief Return PWM brightness to apply when the bulb is turned on.
 */
static zb_uint8_t light_bulb_on_brightness(void)
{
	zb_uint8_t level = dev_ctx.level_control_attr.current_level;

	if (level == 0U) {
		level = s_last_on_level;
	}

	return level;
}

/**@brief Function for setting the light bulb brightness.
 *
 * @param[in] new_level   Light bulb brightness value.
 */
static void level_control_set_value(zb_uint16_t new_level)
{
	LOG_INF("Set level value: %i", new_level);

	if (new_level > 0U) {
		s_last_on_level = new_level;
	}

	ZB_ZCL_SET_ATTRIBUTE(DIMMABLE_LIGHT_ENDPOINT, ZB_ZCL_CLUSTER_ID_LEVEL_CONTROL, ZB_ZCL_CLUSTER_SERVER_ROLE,
			     ZB_ZCL_ATTR_LEVEL_CONTROL_CURRENT_LEVEL_ID, (zb_uint8_t *)&new_level, ZB_FALSE);

	light_bulb_set_brightness(new_level);
}

/**@brief Function for turning ON/OFF the light bulb.
 *
 * @param[in]   on   Boolean light bulb state.
 */
static void on_off_set_value(zb_bool_t on)
{
	LOG_INF("Set ON/OFF value: %i", on);

	ZB_ZCL_SET_ATTRIBUTE(DIMMABLE_LIGHT_ENDPOINT, ZB_ZCL_CLUSTER_ID_ON_OFF, ZB_ZCL_CLUSTER_SERVER_ROLE,
			     ZB_ZCL_ATTR_ON_OFF_ON_OFF_ID, (zb_uint8_t *)&on, ZB_FALSE);

	if (on) {
		level_control_set_value(light_bulb_on_brightness());
	} else {
		light_bulb_set_brightness(0U);
	}
}

/**@brief Function to toggle the identify LED.
 *
 * @param  bufid  Unused parameter, required by ZBOSS scheduler API.
 */
static void toggle_identify_led(zb_bufid_t bufid)
{
	static int blink_status;

	matter_zigbee_ui_led_set(MATTER_ZIGBEE_UI_LED_IDENTIFY, ((++blink_status) % 2) != 0);
	ZB_SCHEDULE_APP_ALARM(toggle_identify_led, bufid, ZB_MILLISECONDS_TO_BEACON_INTERVAL(100));
}

/**@brief Function to handle identify notification events on the first endpoint.
 *
 * @param  bufid  Unused parameter, required by ZBOSS scheduler API.
 */
static void identify_cb(zb_bufid_t bufid)
{
	zb_ret_t zb_err_code;

	if (bufid) {
		ZB_SCHEDULE_APP_CALLBACK(toggle_identify_led, bufid);
	} else {
		zb_err_code = ZB_SCHEDULE_APP_ALARM_CANCEL(toggle_identify_led, ZB_ALARM_ANY_PARAM);
		ZVUNUSED(zb_err_code);

		matter_zigbee_ui_led_set(MATTER_ZIGBEE_UI_LED_IDENTIFY, false);
	}
}

/**@brief Function for initializing all clusters attributes.
 */
static void bulb_clusters_attr_init(void)
{
	/* Basic cluster attributes data */
	dev_ctx.basic_attr.zcl_version = ZB_ZCL_VERSION;
	dev_ctx.basic_attr.app_version = BULB_INIT_BASIC_APP_VERSION;
	dev_ctx.basic_attr.stack_version = BULB_INIT_BASIC_STACK_VERSION;
	dev_ctx.basic_attr.hw_version = BULB_INIT_BASIC_HW_VERSION;

	/* Use ZB_ZCL_SET_STRING_VAL to set strings, because the first byte
	 * should contain string length without trailing zero.
	 *
	 * For example "test" string will be encoded as:
	 *   [(0x4), 't', 'e', 's', 't']
	 */
	ZB_ZCL_SET_STRING_VAL(dev_ctx.basic_attr.mf_name, BULB_INIT_BASIC_MANUF_NAME,
			      ZB_ZCL_STRING_CONST_SIZE(BULB_INIT_BASIC_MANUF_NAME));

	ZB_ZCL_SET_STRING_VAL(dev_ctx.basic_attr.model_id, BULB_INIT_BASIC_MODEL_ID,
			      ZB_ZCL_STRING_CONST_SIZE(BULB_INIT_BASIC_MODEL_ID));

	ZB_ZCL_SET_STRING_VAL(dev_ctx.basic_attr.date_code, BULB_INIT_BASIC_DATE_CODE,
			      ZB_ZCL_STRING_CONST_SIZE(BULB_INIT_BASIC_DATE_CODE));

	dev_ctx.basic_attr.power_source = BULB_INIT_BASIC_POWER_SOURCE;

	ZB_ZCL_SET_STRING_VAL(dev_ctx.basic_attr.location_id, BULB_INIT_BASIC_LOCATION_DESC,
			      ZB_ZCL_STRING_CONST_SIZE(BULB_INIT_BASIC_LOCATION_DESC));

	dev_ctx.basic_attr.ph_env = BULB_INIT_BASIC_PH_ENV;

	/* Identify cluster attributes data. */
	dev_ctx.identify_attr.identify_time = ZB_ZCL_IDENTIFY_IDENTIFY_TIME_DEFAULT_VALUE;

	/* On/Off cluster attributes data. */
	dev_ctx.on_off_attr.on_off = (zb_bool_t)ZB_ZCL_ON_OFF_IS_OFF;

	dev_ctx.level_control_attr.current_level = ZB_ZCL_LEVEL_CONTROL_LEVEL_MAX_VALUE;
	dev_ctx.level_control_attr.remaining_time = ZB_ZCL_LEVEL_CONTROL_REMAINING_TIME_DEFAULT_VALUE;

	ZB_ZCL_SET_ATTRIBUTE(DIMMABLE_LIGHT_ENDPOINT, ZB_ZCL_CLUSTER_ID_ON_OFF, ZB_ZCL_CLUSTER_SERVER_ROLE,
			     ZB_ZCL_ATTR_ON_OFF_ON_OFF_ID, (zb_uint8_t *)&dev_ctx.on_off_attr.on_off, ZB_FALSE);

	ZB_ZCL_SET_ATTRIBUTE(DIMMABLE_LIGHT_ENDPOINT, ZB_ZCL_CLUSTER_ID_LEVEL_CONTROL, ZB_ZCL_CLUSTER_SERVER_ROLE,
			     ZB_ZCL_ATTR_LEVEL_CONTROL_CURRENT_LEVEL_ID,
			     (zb_uint8_t *)&dev_ctx.level_control_attr.current_level, ZB_FALSE);
}

#if defined(CONFIG_ZIGBEE_FOTA) || defined(CONFIG_ZIGBEE_BT_DFU)
static void confirm_image(void)
{
	if (!boot_is_img_confirmed()) {
		int ret = boot_write_img_confirmed();

		if (ret) {
			LOG_ERR("Couldn't confirm image: %d", ret);
		} else {
			LOG_INF("Marked image as OK");
		}
	}
}
#endif

#ifdef CONFIG_ZIGBEE_FOTA
static void ota_evt_handler(const struct zigbee_fota_evt *evt)
{
	switch (evt->id) {
	case ZIGBEE_FOTA_EVT_FINISHED:
		LOG_INF("Reboot application.");
		if (IS_ENABLED(CONFIG_RAM_POWER_DOWN_LIBRARY)) {
			power_up_unused_ram();
		}

		sys_reboot(SYS_REBOOT_COLD);
		break;

	case ZIGBEE_FOTA_EVT_ERROR:
		LOG_ERR("OTA image transfer failed.");
		break;

	default:
		break;
	}
}
#endif /* CONFIG_ZIGBEE_FOTA */

/**@brief Callback function for handling ZCL commands.
 *
 * @param[in]   bufid   Reference to Zigbee stack buffer
 *                      used to pass received data.
 */
static void zcl_device_cb(zb_bufid_t bufid)
{
	zb_uint8_t cluster_id;
	zb_uint8_t attr_id;
	zb_zcl_device_callback_param_t *device_cb_param = ZB_BUF_GET_PARAM(bufid, zb_zcl_device_callback_param_t);

	LOG_INF("%s id %hd", __func__, device_cb_param->device_cb_id);

	/* Set default response value. */
	device_cb_param->status = RET_OK;

	switch (device_cb_param->device_cb_id) {
	case ZB_ZCL_OTA_UPGRADE_VALUE_CB_ID:
#ifdef CONFIG_ZIGBEE_FOTA
		zigbee_fota_zcl_cb(bufid);
#else
		device_cb_param->status = RET_NOT_IMPLEMENTED;
#endif
		break;

	case ZB_ZCL_LEVEL_CONTROL_SET_VALUE_CB_ID:
		LOG_INF("Level control setting to %d",
			device_cb_param->cb_param.level_control_set_value_param.new_value);
		level_control_set_value(device_cb_param->cb_param.level_control_set_value_param.new_value);
		break;

	case ZB_ZCL_SET_ATTR_VALUE_CB_ID:
		cluster_id = device_cb_param->cb_param.set_attr_value_param.cluster_id;
		attr_id = device_cb_param->cb_param.set_attr_value_param.attr_id;

		if (cluster_id == ZB_ZCL_CLUSTER_ID_ON_OFF) {
			uint8_t value = device_cb_param->cb_param.set_attr_value_param.values.data8;

			LOG_INF("on/off attribute setting to %hd", value);
			if (attr_id == ZB_ZCL_ATTR_ON_OFF_ON_OFF_ID) {
				on_off_set_value((zb_bool_t)value);
			}
		} else if (cluster_id == ZB_ZCL_CLUSTER_ID_LEVEL_CONTROL) {
			uint16_t value = device_cb_param->cb_param.set_attr_value_param.values.data16;

			LOG_INF("level control attribute setting to %hd", value);
			if (attr_id == ZB_ZCL_ATTR_LEVEL_CONTROL_CURRENT_LEVEL_ID) {
				level_control_set_value(value);
			}
		} else {
			/* Other clusters can be processed here */
			LOG_INF("Unhandled cluster attribute id: %d", cluster_id);
			device_cb_param->status = RET_NOT_IMPLEMENTED;
		}
		break;

	default:
#ifdef CONFIG_ZIGBEE_SCENES
		if (zcl_scenes_cb(bufid) == ZB_FALSE) {
			device_cb_param->status = RET_NOT_IMPLEMENTED;
		}
#else
		device_cb_param->status = RET_NOT_IMPLEMENTED;
#endif
		break;
	}

	LOG_INF("%s status: %hd", __func__, device_cb_param->status);
}

/**@brief Zigbee stack event handler.
 *
 * @param[in]   bufid   Reference to the Zigbee stack buffer
 *                      used to pass signal.
 */
void zboss_signal_handler(zb_bufid_t bufid)
{
#ifdef CONFIG_ZIGBEE_FOTA
	zigbee_fota_signal_handler(bufid);
#endif

	/* Update network status LED. */
	matter_zigbee_ui_zigbee_led_update(bufid);

#if defined(CONFIG_ZIGBEE_TOUCHLINK_TARGET)
	zigbee_touchlink_target_signal_handler(bufid);
#endif

	ZB_ERROR_CHECK(zigbee_default_signal_handler(bufid));

	/* All callbacks should either reuse or free passed buffers.
	 * If bufid == 0, the buffer is invalid (not passed).
	 */
	if (bufid) {
		zb_buf_free(bufid);
	}
}

extern "C" int ZigbeeStart(void)
{
#ifdef CONFIG_ZIGBEE_SCENES
	int err;
#endif

	LOG_INF("Starting Zigbee R23 Light Bulb example");

	/* Register callback for handling ZCL commands. */
	ZB_ZCL_REGISTER_DEVICE_CB(zcl_device_cb);

	/* Register dimmer switch device context (endpoints). */
	ZB_AF_REGISTER_DEVICE_CTX(&dimmable_light_ctx);

	bulb_clusters_attr_init();

	if (dev_ctx.on_off_attr.on_off) {
		level_control_set_value(dev_ctx.level_control_attr.current_level);
	} else {
		/* Keep CurrentLevel at its default; only drive PWM off. */
		light_bulb_set_brightness(0U);
	}

#if defined(CONFIG_ZIGBEE_FOTA) || defined(CONFIG_ZIGBEE_BT_DFU)
	confirm_image();
#endif

#ifdef CONFIG_ZIGBEE_FOTA
	zigbee_fota_init(ota_evt_handler);
#endif

#ifdef CONFIG_ZIGBEE_BT_DFU
	zigbee_bt_dfu_init();
#endif

	/* Register handler to identify notifications. */
	ZB_AF_SET_IDENTIFY_NOTIFICATION_HANDLER(DIMMABLE_LIGHT_ENDPOINT, identify_cb);
#ifdef CONFIG_ZIGBEE_FOTA
	ZB_AF_SET_IDENTIFY_NOTIFICATION_HANDLER(CONFIG_ZIGBEE_FOTA_ENDPOINT, identify_cb);
#endif

#ifdef CONFIG_ZIGBEE_SCENES
	/* Initialize ZCL scene table */
	zcl_scenes_init();

	/* Settings should be loaded after zcl_scenes_init */
	err = settings_load();
	if (err) {
		LOG_ERR("settings loading failed");
	}
#endif

	/* Start Zigbee default thread */
	zigbee_enable();

	LOG_INF("Zigbee R23 Light Bulb example started");

	while (1) {
		k_sleep(K_FOREVER);
	}

	return 0;
}
```
